VERSION 5.7 ;
  NOWIREEXTENSIONATPIN ON ;
  DIVIDERCHAR "/" ;
  BUSBITCHARS "[]" ;
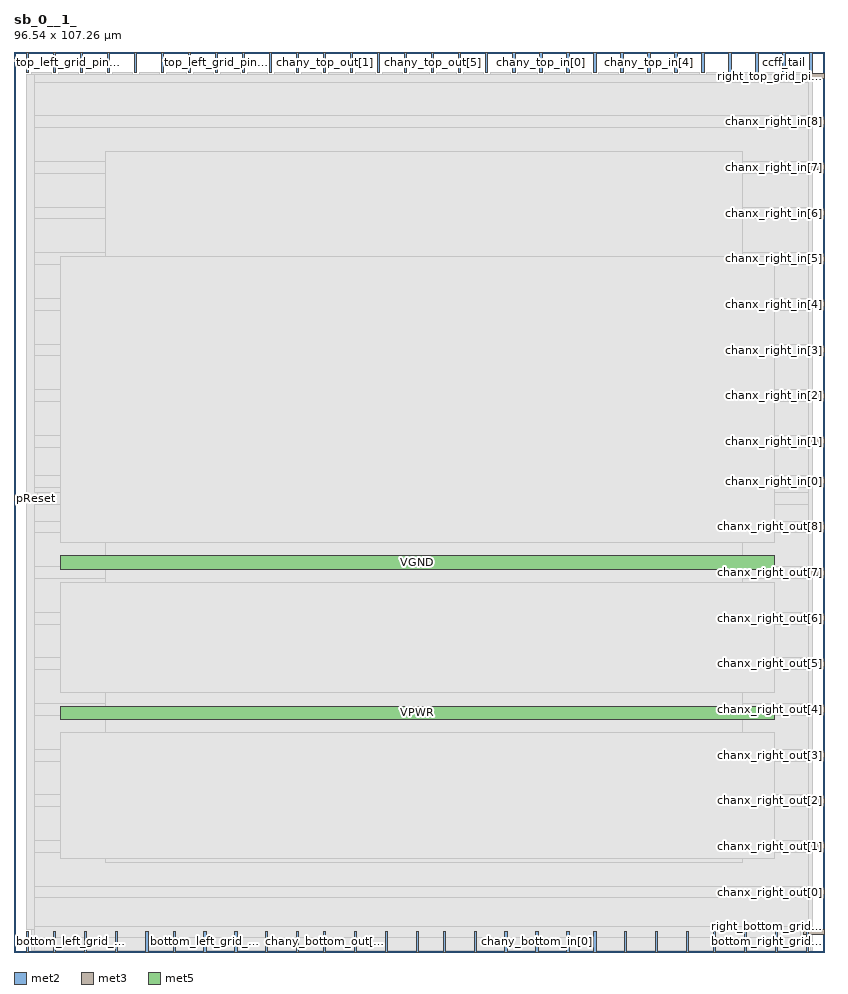
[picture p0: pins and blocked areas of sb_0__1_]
MACRO sb_0__1_
  CLASS BLOCK ;
  FOREIGN sb_0__1_ ;
  ORIGIN 0.000 0.000 ;
  SIZE 96.540 BY 107.260 ;
  PIN bottom_left_grid_pin_11_
    DIRECTION INPUT ;
    PORT
      LAYER met2 ;
        RECT 18.950 0.000 19.230 2.400 ;
    END
  END bottom_left_grid_pin_11_
  PIN bottom_left_grid_pin_13_
    DIRECTION INPUT ;
    PORT
      LAYER met2 ;
        RECT 22.630 0.000 22.910 2.400 ;
    END
  END bottom_left_grid_pin_13_
  PIN bottom_left_grid_pin_15_
    DIRECTION INPUT ;
    PORT
      LAYER met2 ;
        RECT 26.310 0.000 26.590 2.400 ;
    END
  END bottom_left_grid_pin_15_
  PIN bottom_left_grid_pin_1_
    DIRECTION INPUT ;
    PORT
      LAYER met2 ;
        RECT 1.470 0.000 1.750 2.400 ;
    END
  END bottom_left_grid_pin_1_
  PIN bottom_left_grid_pin_3_
    DIRECTION INPUT ;
    PORT
      LAYER met2 ;
        RECT 4.690 0.000 4.970 2.400 ;
    END
  END bottom_left_grid_pin_3_
  PIN bottom_left_grid_pin_5_
    DIRECTION INPUT ;
    PORT
      LAYER met2 ;
        RECT 8.370 0.000 8.650 2.400 ;
    END
  END bottom_left_grid_pin_5_
  PIN bottom_left_grid_pin_7_
    DIRECTION INPUT ;
    PORT
      LAYER met2 ;
        RECT 12.050 0.000 12.330 2.400 ;
    END
  END bottom_left_grid_pin_7_
  PIN bottom_left_grid_pin_9_
    DIRECTION INPUT ;
    PORT
      LAYER met2 ;
        RECT 15.730 0.000 16.010 2.400 ;
    END
  END bottom_left_grid_pin_9_
  PIN bottom_right_grid_pin_11_
    DIRECTION INPUT ;
    PORT
      LAYER met2 ;
        RECT 94.390 0.000 94.670 2.400 ;
    END
  END bottom_right_grid_pin_11_
  PIN ccff_head
    DIRECTION INPUT ;
    PORT
      LAYER met2 ;
        RECT 1.470 104.860 1.750 107.260 ;
    END
  END ccff_head
  PIN ccff_tail
    DIRECTION OUTPUT TRISTATE ;
    PORT
      LAYER met2 ;
        RECT 91.630 104.860 91.910 107.260 ;
    END
  END ccff_tail
  PIN chanx_right_in[0]
    DIRECTION INPUT ;
    PORT
      LAYER met3 ;
        RECT 94.140 55.800 96.540 56.400 ;
    END
  END chanx_right_in[0]
  PIN chanx_right_in[1]
    DIRECTION INPUT ;
    PORT
      LAYER met3 ;
        RECT 94.140 60.560 96.540 61.160 ;
    END
  END chanx_right_in[1]
  PIN chanx_right_in[2]
    DIRECTION INPUT ;
    PORT
      LAYER met3 ;
        RECT 94.140 66.000 96.540 66.600 ;
    END
  END chanx_right_in[2]
  PIN chanx_right_in[3]
    DIRECTION INPUT ;
    PORT
      LAYER met3 ;
        RECT 94.140 71.440 96.540 72.040 ;
    END
  END chanx_right_in[3]
  PIN chanx_right_in[4]
    DIRECTION INPUT ;
    PORT
      LAYER met3 ;
        RECT 94.140 76.880 96.540 77.480 ;
    END
  END chanx_right_in[4]
  PIN chanx_right_in[5]
    DIRECTION INPUT ;
    PORT
      LAYER met3 ;
        RECT 94.140 82.320 96.540 82.920 ;
    END
  END chanx_right_in[5]
  PIN chanx_right_in[6]
    DIRECTION INPUT ;
    PORT
      LAYER met3 ;
        RECT 94.140 87.760 96.540 88.360 ;
    END
  END chanx_right_in[6]
  PIN chanx_right_in[7]
    DIRECTION INPUT ;
    PORT
      LAYER met3 ;
        RECT 94.140 93.200 96.540 93.800 ;
    END
  END chanx_right_in[7]
  PIN chanx_right_in[8]
    DIRECTION INPUT ;
    PORT
      LAYER met3 ;
        RECT 94.140 98.640 96.540 99.240 ;
    END
  END chanx_right_in[8]
  PIN chanx_right_out[0]
    DIRECTION OUTPUT TRISTATE ;
    PORT
      LAYER met3 ;
        RECT 94.140 6.840 96.540 7.440 ;
    END
  END chanx_right_out[0]
  PIN chanx_right_out[1]
    DIRECTION OUTPUT TRISTATE ;
    PORT
      LAYER met3 ;
        RECT 94.140 12.280 96.540 12.880 ;
    END
  END chanx_right_out[1]
  PIN chanx_right_out[2]
    DIRECTION OUTPUT TRISTATE ;
    PORT
      LAYER met3 ;
        RECT 94.140 17.720 96.540 18.320 ;
    END
  END chanx_right_out[2]
  PIN chanx_right_out[3]
    DIRECTION OUTPUT TRISTATE ;
    PORT
      LAYER met3 ;
        RECT 94.140 23.160 96.540 23.760 ;
    END
  END chanx_right_out[3]
  PIN chanx_right_out[4]
    DIRECTION OUTPUT TRISTATE ;
    PORT
      LAYER met3 ;
        RECT 94.140 28.600 96.540 29.200 ;
    END
  END chanx_right_out[4]
  PIN chanx_right_out[5]
    DIRECTION OUTPUT TRISTATE ;
    PORT
      LAYER met3 ;
        RECT 94.140 34.040 96.540 34.640 ;
    END
  END chanx_right_out[5]
  PIN chanx_right_out[6]
    DIRECTION OUTPUT TRISTATE ;
    PORT
      LAYER met3 ;
        RECT 94.140 39.480 96.540 40.080 ;
    END
  END chanx_right_out[6]
  PIN chanx_right_out[7]
    DIRECTION OUTPUT TRISTATE ;
    PORT
      LAYER met3 ;
        RECT 94.140 44.920 96.540 45.520 ;
    END
  END chanx_right_out[7]
  PIN chanx_right_out[8]
    DIRECTION OUTPUT TRISTATE ;
    PORT
      LAYER met3 ;
        RECT 94.140 50.360 96.540 50.960 ;
    END
  END chanx_right_out[8]
  PIN chany_bottom_in[0]
    DIRECTION INPUT ;
    PORT
      LAYER met2 ;
        RECT 62.190 0.000 62.470 2.400 ;
    END
  END chany_bottom_in[0]
  PIN chany_bottom_in[1]
    DIRECTION INPUT ;
    PORT
      LAYER met2 ;
        RECT 65.870 0.000 66.150 2.400 ;
    END
  END chany_bottom_in[1]
  PIN chany_bottom_in[2]
    DIRECTION INPUT ;
    PORT
      LAYER met2 ;
        RECT 69.090 0.000 69.370 2.400 ;
    END
  END chany_bottom_in[2]
  PIN chany_bottom_in[3]
    DIRECTION INPUT ;
    PORT
      LAYER met2 ;
        RECT 72.770 0.000 73.050 2.400 ;
    END
  END chany_bottom_in[3]
  PIN chany_bottom_in[4]
    DIRECTION INPUT ;
    PORT
      LAYER met2 ;
        RECT 76.450 0.000 76.730 2.400 ;
    END
  END chany_bottom_in[4]
  PIN chany_bottom_in[5]
    DIRECTION INPUT ;
    PORT
      LAYER met2 ;
        RECT 80.130 0.000 80.410 2.400 ;
    END
  END chany_bottom_in[5]
  PIN chany_bottom_in[6]
    DIRECTION INPUT ;
    PORT
      LAYER met2 ;
        RECT 83.350 0.000 83.630 2.400 ;
    END
  END chany_bottom_in[6]
  PIN chany_bottom_in[7]
    DIRECTION INPUT ;
    PORT
      LAYER met2 ;
        RECT 87.030 0.000 87.310 2.400 ;
    END
  END chany_bottom_in[7]
  PIN chany_bottom_in[8]
    DIRECTION INPUT ;
    PORT
      LAYER met2 ;
        RECT 90.710 0.000 90.990 2.400 ;
    END
  END chany_bottom_in[8]
  PIN chany_bottom_out[0]
    DIRECTION OUTPUT TRISTATE ;
    PORT
      LAYER met2 ;
        RECT 29.990 0.000 30.270 2.400 ;
    END
  END chany_bottom_out[0]
  PIN chany_bottom_out[1]
    DIRECTION OUTPUT TRISTATE ;
    PORT
      LAYER met2 ;
        RECT 33.670 0.000 33.950 2.400 ;
    END
  END chany_bottom_out[1]
  PIN chany_bottom_out[2]
    DIRECTION OUTPUT TRISTATE ;
    PORT
      LAYER met2 ;
        RECT 36.890 0.000 37.170 2.400 ;
    END
  END chany_bottom_out[2]
  PIN chany_bottom_out[3]
    DIRECTION OUTPUT TRISTATE ;
    PORT
      LAYER met2 ;
        RECT 40.570 0.000 40.850 2.400 ;
    END
  END chany_bottom_out[3]
  PIN chany_bottom_out[4]
    DIRECTION OUTPUT TRISTATE ;
    PORT
      LAYER met2 ;
        RECT 44.250 0.000 44.530 2.400 ;
    END
  END chany_bottom_out[4]
  PIN chany_bottom_out[5]
    DIRECTION OUTPUT TRISTATE ;
    PORT
      LAYER met2 ;
        RECT 47.930 0.000 48.210 2.400 ;
    END
  END chany_bottom_out[5]
  PIN chany_bottom_out[6]
    DIRECTION OUTPUT TRISTATE ;
    PORT
      LAYER met2 ;
        RECT 51.150 0.000 51.430 2.400 ;
    END
  END chany_bottom_out[6]
  PIN chany_bottom_out[7]
    DIRECTION OUTPUT TRISTATE ;
    PORT
      LAYER met2 ;
        RECT 54.830 0.000 55.110 2.400 ;
    END
  END chany_bottom_out[7]
  PIN chany_bottom_out[8]
    DIRECTION OUTPUT TRISTATE ;
    PORT
      LAYER met2 ;
        RECT 58.510 0.000 58.790 2.400 ;
    END
  END chany_bottom_out[8]
  PIN chany_top_in[0]
    DIRECTION INPUT ;
    PORT
      LAYER met2 ;
        RECT 62.650 104.860 62.930 107.260 ;
    END
  END chany_top_in[0]
  PIN chany_top_in[1]
    DIRECTION INPUT ;
    PORT
      LAYER met2 ;
        RECT 65.870 104.860 66.150 107.260 ;
    END
  END chany_top_in[1]
  PIN chany_top_in[2]
    DIRECTION INPUT ;
    PORT
      LAYER met2 ;
        RECT 69.090 104.860 69.370 107.260 ;
    END
  END chany_top_in[2]
  PIN chany_top_in[3]
    DIRECTION INPUT ;
    PORT
      LAYER met2 ;
        RECT 72.310 104.860 72.590 107.260 ;
    END
  END chany_top_in[3]
  PIN chany_top_in[4]
    DIRECTION INPUT ;
    PORT
      LAYER met2 ;
        RECT 75.530 104.860 75.810 107.260 ;
    END
  END chany_top_in[4]
  PIN chany_top_in[5]
    DIRECTION INPUT ;
    PORT
      LAYER met2 ;
        RECT 78.750 104.860 79.030 107.260 ;
    END
  END chany_top_in[5]
  PIN chany_top_in[6]
    DIRECTION INPUT ;
    PORT
      LAYER met2 ;
        RECT 81.970 104.860 82.250 107.260 ;
    END
  END chany_top_in[6]
  PIN chany_top_in[7]
    DIRECTION INPUT ;
    PORT
      LAYER met2 ;
        RECT 85.190 104.860 85.470 107.260 ;
    END
  END chany_top_in[7]
  PIN chany_top_in[8]
    DIRECTION INPUT ;
    PORT
      LAYER met2 ;
        RECT 88.410 104.860 88.690 107.260 ;
    END
  END chany_top_in[8]
  PIN chany_top_out[0]
    DIRECTION OUTPUT TRISTATE ;
    PORT
      LAYER met2 ;
        RECT 33.670 104.860 33.950 107.260 ;
    END
  END chany_top_out[0]
  PIN chany_top_out[1]
    DIRECTION OUTPUT TRISTATE ;
    PORT
      LAYER met2 ;
        RECT 36.890 104.860 37.170 107.260 ;
    END
  END chany_top_out[1]
  PIN chany_top_out[2]
    DIRECTION OUTPUT TRISTATE ;
    PORT
      LAYER met2 ;
        RECT 40.110 104.860 40.390 107.260 ;
    END
  END chany_top_out[2]
  PIN chany_top_out[3]
    DIRECTION OUTPUT TRISTATE ;
    PORT
      LAYER met2 ;
        RECT 43.330 104.860 43.610 107.260 ;
    END
  END chany_top_out[3]
  PIN chany_top_out[4]
    DIRECTION OUTPUT TRISTATE ;
    PORT
      LAYER met2 ;
        RECT 46.550 104.860 46.830 107.260 ;
    END
  END chany_top_out[4]
  PIN chany_top_out[5]
    DIRECTION OUTPUT TRISTATE ;
    PORT
      LAYER met2 ;
        RECT 49.770 104.860 50.050 107.260 ;
    END
  END chany_top_out[5]
  PIN chany_top_out[6]
    DIRECTION OUTPUT TRISTATE ;
    PORT
      LAYER met2 ;
        RECT 52.990 104.860 53.270 107.260 ;
    END
  END chany_top_out[6]
  PIN chany_top_out[7]
    DIRECTION OUTPUT TRISTATE ;
    PORT
      LAYER met2 ;
        RECT 56.210 104.860 56.490 107.260 ;
    END
  END chany_top_out[7]
  PIN chany_top_out[8]
    DIRECTION OUTPUT TRISTATE ;
    PORT
      LAYER met2 ;
        RECT 59.430 104.860 59.710 107.260 ;
    END
  END chany_top_out[8]
  PIN pReset
    DIRECTION INPUT ;
    PORT
      LAYER met3 ;
        RECT 0.000 53.760 2.400 54.360 ;
    END
  END pReset
  PIN prog_clk
    DIRECTION INPUT ;
    PORT
      LAYER met2 ;
        RECT 30.450 104.860 30.730 107.260 ;
    END
  END prog_clk
  PIN right_bottom_grid_pin_12_
    DIRECTION INPUT ;
    PORT
      LAYER met3 ;
        RECT 94.140 2.080 96.540 2.680 ;
    END
  END right_bottom_grid_pin_12_
  PIN right_top_grid_pin_10_
    DIRECTION INPUT ;
    PORT
      LAYER met3 ;
        RECT 94.140 104.080 96.540 104.680 ;
    END
  END right_top_grid_pin_10_
  PIN top_left_grid_pin_11_
    DIRECTION INPUT ;
    PORT
      LAYER met2 ;
        RECT 20.790 104.860 21.070 107.260 ;
    END
  END top_left_grid_pin_11_
  PIN top_left_grid_pin_13_
    DIRECTION INPUT ;
    PORT
      LAYER met2 ;
        RECT 24.010 104.860 24.290 107.260 ;
    END
  END top_left_grid_pin_13_
  PIN top_left_grid_pin_15_
    DIRECTION INPUT ;
    PORT
      LAYER met2 ;
        RECT 27.230 104.860 27.510 107.260 ;
    END
  END top_left_grid_pin_15_
  PIN top_left_grid_pin_1_
    DIRECTION INPUT ;
    PORT
      LAYER met2 ;
        RECT 4.690 104.860 4.970 107.260 ;
    END
  END top_left_grid_pin_1_
  PIN top_left_grid_pin_3_
    DIRECTION INPUT ;
    PORT
      LAYER met2 ;
        RECT 7.910 104.860 8.190 107.260 ;
    END
  END top_left_grid_pin_3_
  PIN top_left_grid_pin_5_
    DIRECTION INPUT ;
    PORT
      LAYER met2 ;
        RECT 11.130 104.860 11.410 107.260 ;
    END
  END top_left_grid_pin_5_
  PIN top_left_grid_pin_7_
    DIRECTION INPUT ;
    PORT
      LAYER met2 ;
        RECT 14.350 104.860 14.630 107.260 ;
    END
  END top_left_grid_pin_7_
  PIN top_left_grid_pin_9_
    DIRECTION INPUT ;
    PORT
      LAYER met2 ;
        RECT 17.570 104.860 17.850 107.260 ;
    END
  END top_left_grid_pin_9_
  PIN top_right_grid_pin_11_
    DIRECTION INPUT ;
    PORT
      LAYER met2 ;
        RECT 94.850 104.860 95.130 107.260 ;
    END
  END top_right_grid_pin_11_
  PIN VPWR
    DIRECTION INPUT ;
    USE POWER ;
    PORT
      LAYER met5 ;
        RECT 5.520 27.715 90.620 29.315 ;
    END
  END VPWR
  PIN VGND
    DIRECTION INPUT ;
    USE GROUND ;
    PORT
      LAYER met5 ;
        RECT 5.520 45.595 90.620 47.195 ;
    END
  END VGND
  OBS
      LAYER li1 ;
        RECT 5.520 10.795 90.620 95.285 ;
      LAYER met1 ;
        RECT 1.450 2.760 95.150 96.520 ;
      LAYER met2 ;
        RECT 2.030 104.580 4.410 104.860 ;
        RECT 5.250 104.580 7.630 104.860 ;
        RECT 8.470 104.580 10.850 104.860 ;
        RECT 11.690 104.580 14.070 104.860 ;
        RECT 14.910 104.580 17.290 104.860 ;
        RECT 18.130 104.580 20.510 104.860 ;
        RECT 21.350 104.580 23.730 104.860 ;
        RECT 24.570 104.580 26.950 104.860 ;
        RECT 27.790 104.580 30.170 104.860 ;
        RECT 31.010 104.580 33.390 104.860 ;
        RECT 34.230 104.580 36.610 104.860 ;
        RECT 37.450 104.580 39.830 104.860 ;
        RECT 40.670 104.580 43.050 104.860 ;
        RECT 43.890 104.580 46.270 104.860 ;
        RECT 47.110 104.580 49.490 104.860 ;
        RECT 50.330 104.580 52.710 104.860 ;
        RECT 53.550 104.580 55.930 104.860 ;
        RECT 56.770 104.580 59.150 104.860 ;
        RECT 59.990 104.580 62.370 104.860 ;
        RECT 63.210 104.580 65.590 104.860 ;
        RECT 66.430 104.580 68.810 104.860 ;
        RECT 69.650 104.580 72.030 104.860 ;
        RECT 72.870 104.580 75.250 104.860 ;
        RECT 76.090 104.580 78.470 104.860 ;
        RECT 79.310 104.580 81.690 104.860 ;
        RECT 82.530 104.580 84.910 104.860 ;
        RECT 85.750 104.580 88.130 104.860 ;
        RECT 88.970 104.580 91.350 104.860 ;
        RECT 92.190 104.580 94.570 104.860 ;
        RECT 1.480 2.680 95.120 104.580 ;
        RECT 2.030 0.155 4.410 2.680 ;
        RECT 5.250 0.155 8.090 2.680 ;
        RECT 8.930 0.155 11.770 2.680 ;
        RECT 12.610 0.155 15.450 2.680 ;
        RECT 16.290 0.155 18.670 2.680 ;
        RECT 19.510 0.155 22.350 2.680 ;
        RECT 23.190 0.155 26.030 2.680 ;
        RECT 26.870 0.155 29.710 2.680 ;
        RECT 30.550 0.155 33.390 2.680 ;
        RECT 34.230 0.155 36.610 2.680 ;
        RECT 37.450 0.155 40.290 2.680 ;
        RECT 41.130 0.155 43.970 2.680 ;
        RECT 44.810 0.155 47.650 2.680 ;
        RECT 48.490 0.155 50.870 2.680 ;
        RECT 51.710 0.155 54.550 2.680 ;
        RECT 55.390 0.155 58.230 2.680 ;
        RECT 59.070 0.155 61.910 2.680 ;
        RECT 62.750 0.155 65.590 2.680 ;
        RECT 66.430 0.155 68.810 2.680 ;
        RECT 69.650 0.155 72.490 2.680 ;
        RECT 73.330 0.155 76.170 2.680 ;
        RECT 77.010 0.155 79.850 2.680 ;
        RECT 80.690 0.155 83.070 2.680 ;
        RECT 83.910 0.155 86.750 2.680 ;
        RECT 87.590 0.155 90.430 2.680 ;
        RECT 91.270 0.155 94.110 2.680 ;
        RECT 94.950 0.155 95.120 2.680 ;
      LAYER met3 ;
        RECT 2.400 103.680 93.740 104.545 ;
        RECT 2.400 99.640 94.695 103.680 ;
        RECT 2.400 98.240 93.740 99.640 ;
        RECT 2.400 94.200 94.695 98.240 ;
        RECT 2.400 92.800 93.740 94.200 ;
        RECT 2.400 88.760 94.695 92.800 ;
        RECT 2.400 87.360 93.740 88.760 ;
        RECT 2.400 83.320 94.695 87.360 ;
        RECT 2.400 81.920 93.740 83.320 ;
        RECT 2.400 77.880 94.695 81.920 ;
        RECT 2.400 76.480 93.740 77.880 ;
        RECT 2.400 72.440 94.695 76.480 ;
        RECT 2.400 71.040 93.740 72.440 ;
        RECT 2.400 67.000 94.695 71.040 ;
        RECT 2.400 65.600 93.740 67.000 ;
        RECT 2.400 61.560 94.695 65.600 ;
        RECT 2.400 60.160 93.740 61.560 ;
        RECT 2.400 56.800 94.695 60.160 ;
        RECT 2.400 55.400 93.740 56.800 ;
        RECT 2.400 54.760 94.695 55.400 ;
        RECT 2.800 53.360 94.695 54.760 ;
        RECT 2.400 51.360 94.695 53.360 ;
        RECT 2.400 49.960 93.740 51.360 ;
        RECT 2.400 45.920 94.695 49.960 ;
        RECT 2.400 44.520 93.740 45.920 ;
        RECT 2.400 40.480 94.695 44.520 ;
        RECT 2.400 39.080 93.740 40.480 ;
        RECT 2.400 35.040 94.695 39.080 ;
        RECT 2.400 33.640 93.740 35.040 ;
        RECT 2.400 29.600 94.695 33.640 ;
        RECT 2.400 28.200 93.740 29.600 ;
        RECT 2.400 24.160 94.695 28.200 ;
        RECT 2.400 22.760 93.740 24.160 ;
        RECT 2.400 18.720 94.695 22.760 ;
        RECT 2.400 17.320 93.740 18.720 ;
        RECT 2.400 13.280 94.695 17.320 ;
        RECT 2.400 11.880 93.740 13.280 ;
        RECT 2.400 7.840 94.695 11.880 ;
        RECT 2.400 6.440 93.740 7.840 ;
        RECT 2.400 3.080 94.695 6.440 ;
        RECT 2.400 1.680 93.740 3.080 ;
        RECT 2.400 0.175 94.695 1.680 ;
      LAYER met4 ;
        RECT 10.910 10.640 86.770 95.440 ;
      LAYER met5 ;
        RECT 5.520 48.795 90.620 82.945 ;
        RECT 5.520 30.915 90.620 43.995 ;
        RECT 5.520 11.100 90.620 26.115 ;
  END
END sb_0__1_
END LIBRARY

